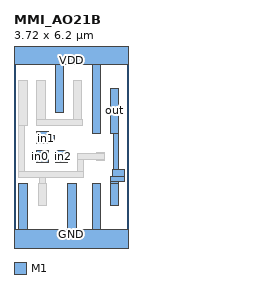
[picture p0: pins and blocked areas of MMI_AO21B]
MACRO MMI_AO21B
	CLASS CORE ;
	FOREIGN MMI_AO21B 0 0 ;
	SIZE 3.72 BY 6.2 ;
	SYMMETRY X Y ;
	SITE CORE1 ;
	PIN out
		DIRECTION output ;
		USE SIGNAL ;
		PORT
			LAYER M1 ;
			RECT 3.145 3.54 3.425 5.01 ;
			LAYER M1 ;
			RECT 3.235 2.36 3.425 3.54 ;
			LAYER M1 ;
			RECT 3.22 2.13 3.6 2.36 ;
			LAYER M1 ;
			RECT 3.15 1.98 3.6 2.13 ;
			LAYER M1 ;
			RECT 3.15 1.905 3.425 1.98 ;
			LAYER M1 ;
			RECT 3.145 1.205 3.425 1.905 ;
		END
		AntennaDiffArea 0.91245 ;
	END out
	PIN in1
		DIRECTION input ;
		USE SIGNAL ;
		PORT
			LAYER M1 ;
			RECT 0.74 3.51 1.12 3.6 ;
			LAYER M1 ;
			RECT 0.74 3.465 1.27 3.51 ;
			LAYER M1 ;
			RECT 0.74 3.27 1.33 3.465 ;
			LAYER M1 ;
			RECT 0.74 3.23 1.27 3.27 ;
			LAYER M1 ;
			RECT 0.74 3.22 1.12 3.23 ;
		END
		AntennaGateArea 0.3465 ;
	END in1
	PIN GND
		DIRECTION inout ;
		USE GROUND ;
		PORT
			LAYER M1 ;
			RECT 0.16 0.42 0.44 1.905 ;
			LAYER M1 ;
			RECT 1.755 0.42 2.035 1.905 ;
			LAYER M1 ;
			RECT 2.555 0.42 2.835 1.905 ;
			LAYER M1 ;
			RECT 0 -0.42 3.72 0.42 ;
		END
	END GND
	PIN in2
		DIRECTION input ;
		USE SIGNAL ;
		PORT
			LAYER M1 ;
			RECT 1.36 2.93 1.74 2.98 ;
			LAYER M1 ;
			RECT 1.36 2.65 1.84 2.93 ;
			LAYER M1 ;
			RECT 1.36 2.6 1.74 2.65 ;
		END
		AntennaGateArea 0.3465 ;
	END in2
	PIN VDD
		DIRECTION inout ;
		USE POWER ;
		PORT
			LAYER M1 ;
			RECT 0 5.78 3.72 6.62 ;
			LAYER M1 ;
			RECT 1.34 4.225 1.62 5.78 ;
			LAYER M1 ;
			RECT 2.555 3.54 2.835 5.78 ;
		END
	END VDD
	PIN in0
		DIRECTION input ;
		USE SIGNAL ;
		PORT
			LAYER M1 ;
			RECT 0.74 2.93 1.12 2.98 ;
			LAYER M1 ;
			RECT 0.56 2.65 1.12 2.93 ;
			LAYER M1 ;
			RECT 0.74 2.6 1.12 2.65 ;
		END
		AntennaGateArea 0.28875 ;
	END in0
	OBS
		LAYER M1 ;
		RECT 0.16 3.815 0.44 5.285 ;
		LAYER M1 ;
		RECT 0.75 4.005 1.03 5.285 ;
		LAYER M1 ;
		RECT 1.93 4.005 2.21 5.285 ;
		LAYER M1 ;
		RECT 0.75 3.815 2.245 4.005 ;
		LAYER M1 ;
		RECT 0.16 2.31 0.355 3.815 ;
		LAYER M1 ;
		RECT 2.68 2.885 2.96 2.93 ;
		LAYER M1 ;
		RECT 2.075 2.695 2.96 2.885 ;
		LAYER M1 ;
		RECT 2.075 2.31 2.265 2.695 ;
		LAYER M1 ;
		RECT 2.68 2.65 2.96 2.695 ;
		LAYER M1 ;
		RECT 0.16 2.115 2.265 2.31 ;
		LAYER M1 ;
		RECT 0.84 1.905 1.03 2.115 ;
		LAYER M1 ;
		RECT 0.795 1.205 1.075 1.905 ;
	END
END MMI_AO21B
